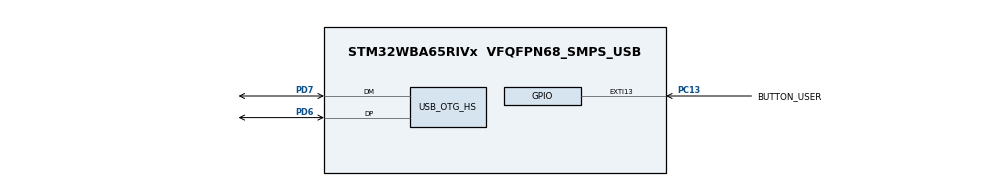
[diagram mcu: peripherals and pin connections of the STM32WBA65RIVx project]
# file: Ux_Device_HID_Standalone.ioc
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CORTEX_M33_NS.userName=CORTEX_M33
Mcu.Family=STM32WBA
Mcu.Name=STM32WBA65RIVx
Mcu.Package=VFQFPN68_SMPS_USB
NVIC.EXTI13_IRQn=true\:7\:0\:true\:false\:true\:true\:true\:true
NVIC.PriorityGroup=NVIC_PRIORITYGROUP_4
NVIC.USB_OTG_HS_IRQn=true\:6\:0\:true\:false\:true\:true\:true\:true
OSC_IN.Mode=HSE-External-Oscillator
OSC_IN.PinAttribute=CortexM33
OSC_IN.Signal=RCC_OSC_IN
OSC_OUT.Mode=HSE-External-Oscillator
OSC_OUT.PinAttribute=CortexM33
OSC_OUT.Signal=RCC_OSC_OUT
PC13.GPIO_Label=BUTTON_USER
PC13.GPIO_ModeDefaultEXTI=GPIO_MODE_IT_FALLING
PC13.GPIO_PuPd=GPIO_PULLUP
PC13.PinAttribute=Free
PC13.Signal=GPXTI13
PD6.Mode=Internal_Phy_Device
PD6.PinAttribute=CortexM33
PD6.Signal=USB_OTG_HS_DP
PD7.Mode=Internal_Phy_Device
PD7.PinAttribute=CortexM33
PD7.Signal=USB_OTG_HS_DM
ProjectManager.HeapSize=0x200
ProjectManager.StackSize=0x400
ProjectManager.TargetToolchain=EWARM V9.60
RCC.ADCFreq_Value=100000000
RCC.AHB5CLKDivider=DIV4
RCC.AHBFreq_Value=100000000
RCC.APB1Freq_Value=100000000
RCC.APB1TimFreq_Value=100000000
RCC.APB2Freq_Value=100000000
RCC.APB2TimFreq_Value=100000000
RCC.CortexFreq_Value=12500000
RCC.HCLKFreq_Value=100000000
RCC.HSE_VALUE=32000000
RCC.HSI_VALUE=16000000
RCC.LSE_VALUE=32768
RCC.LSI1_VALUE=32000
RCC.LSI2_VALUE=32000
RCC.PLLFRACN=4096
RCC.PLLM=2
RCC.PLLN=12
RCC.PLLSourceVirtual=RCC_PLLSOURCE_HSE
RCC.SYSCLKFreq_VALUE=100000000
RCC.SYSCLKSourceVirtual=RCC_SYSCLKSOURCE_PLLCLK
RCC.VCOOutputFreq_Value=200000000
USBX.BSP.number=1
USBX.Core_System=1
USBX.MAX_POWER_IN_MILLI_AMPER=0
USBX.REG_USBX_DEVICE_CON_CK=0
USBX.USBD_COMPOSITE_USE_IAD=0
USBX.USBD_PRODUCT_STRING=STM32 HID Mouse Device
USBX.USBD_SERIAL_NUMBER=HID001
USBX.USBX_SYS_SIZE=1024 * 4
USBX.UX_ALIGN_MIN=UX_ALIGN_8
USBX.UX_APP_MEM_POOL_SIZE_STANDALONE=1024 * 4
USBX.UX_DEVICE_ENABLED_HS=1
USBX.UX_DEVICE_HID_CORE=1
USBX.UX_DEVICE_HID_MOUSE=1
USBX.UX_Device_Controller=1
USBX.UX_Device_CoreStack=1
USBX.UX_MAX_SLAVE_CLASS_DRIVER=1
USBX.UX_SLAVE_REQUEST_DATA_MAX_LENGTH=512
USBX0.BSP.STBoard=false
USBX0.BSP.api=Unknown
USBX0.BSP.instance=USB_OTG_HS
USBX0.BSP.ip=USB_OTG_HS
USBX0.BSP.mode=Device_Only
USBX0.BSP.name=USB_Device
USBX0.BSP.solution=USB_OTG_HS
USB_OTG_HS.RefClockSelection=SYSCFG_OTG_HS_PHY_CLK_SELECT_6
USB_OTG_HS.VirtualMode=Device_HS
VP_CORTEX_M33_NS_VS_Hclk.Mode=Hclk_Mode
VP_ICACHE_VS_ICACHE.Mode=DirectMappedCache
VP_PWR_VS_SECSignals.Mode=Security/Privilege
VP_USBX_Core_System.Mode=Core_System
VP_USBX_UX\ Device\ Controller_HS.Mode=UX_Device_Controller_HS
VP_USBX_UX\ Device\ CoreStack_HS.Mode=UX_Device_CoreStack_HS
VP_USBX_UX\ Device\ HID_CORE_HS.Mode=UX_Device_class_HID_CORE_HS
VP_USBX_UX\ Device\ HID_MOUSE_HS.Mode=UX_Device_class_HID_MOUSE_HS
board=custom

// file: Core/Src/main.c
/* USER CODE BEGIN Header */
/**
  ******************************************************************************
  * @file           : main.c
  * @brief          : Main program body
  ******************************************************************************
  * @attention
  *
  * Copyright (c) 2024 STMicroelectronics.
  * All rights reserved.
  *
  * This software is licensed under terms that can be found in the LICENSE file
  * in the root directory of this software component.
  * If no LICENSE file comes with this software, it is provided AS-IS.
  *
  ******************************************************************************
  */
/* USER CODE END Header */
#include "main.h"
#include "app_usbx.h"

PCD_HandleTypeDef hpcd_USB_OTG_HS;

void SystemClock_Config(void);
static void MX_GPIO_Init(void);
static void MX_ICACHE_Init(void);

int main(void)
{

  /* MCU Configuration--------------------------------------------------------*/

  /* Reset of all peripherals, Initializes the Flash interface and the Systick. */
  HAL_Init();

  /* Configure the system clock */
  SystemClock_Config();

  /* Initialize all configured peripherals */
  MX_GPIO_Init();
  MX_ICACHE_Init();
  MX_USBX_Init();

  /* Infinite loop */
  while (1)
  {

    /* USER CODE BEGIN 3 */
    USBX_Device_Process(NULL);
  }
  /* USER CODE END 3 */
}

void SystemClock_Config(void)
{
  RCC_OscInitTypeDef RCC_OscInitStruct = {0};
  RCC_ClkInitTypeDef RCC_ClkInitStruct = {0};

  /** Supply configuration update enable
  */
  HAL_PWREx_ConfigSupply(PWR_LDO_SUPPLY);

  /** Configure the main internal regulator output voltage
  */
  if (HAL_PWREx_ControlVoltageScaling(PWR_REGULATOR_VOLTAGE_SCALE1) != HAL_OK)
  {
    Error_Handler();
  }

  /** Initializes the CPU, AHB and APB busses clocks
  */
  RCC_OscInitStruct.OscillatorType = RCC_OSCILLATORTYPE_HSE;
  RCC_OscInitStruct.HSEState = RCC_HSE_ON;
  RCC_OscInitStruct.HSEDiv = RCC_HSE_DIV1;
  RCC_OscInitStruct.PLL1.PLLState = RCC_PLL_ON;
  RCC_OscInitStruct.PLL1.PLLSource = RCC_PLLSOURCE_HSE;
  RCC_OscInitStruct.PLL1.PLLM = 2;
  RCC_OscInitStruct.PLL1.PLLN = 12;
  RCC_OscInitStruct.PLL1.PLLP = 2;
  RCC_OscInitStruct.PLL1.PLLQ = 2;
  RCC_OscInitStruct.PLL1.PLLR = 2;
  RCC_OscInitStruct.PLL1.PLLFractional = 4096;
  if (HAL_RCC_OscConfig(&RCC_OscInitStruct) != HAL_OK)
  {
    Error_Handler();
  }

  /** Initializes the CPU, AHB and APB busses clocks
  */
  RCC_ClkInitStruct.ClockType = RCC_CLOCKTYPE_HCLK|RCC_CLOCKTYPE_SYSCLK
                              |RCC_CLOCKTYPE_PCLK1|RCC_CLOCKTYPE_PCLK2
                              |RCC_CLOCKTYPE_PCLK7|RCC_CLOCKTYPE_HCLK5;
  RCC_ClkInitStruct.SYSCLKSource = RCC_SYSCLKSOURCE_PLLCLK;
  RCC_ClkInitStruct.AHBCLKDivider = RCC_SYSCLK_DIV1;
  RCC_ClkInitStruct.APB1CLKDivider = RCC_HCLK_DIV1;
  RCC_ClkInitStruct.APB2CLKDivider = RCC_HCLK_DIV1;
  RCC_ClkInitStruct.APB7CLKDivider = RCC_HCLK_DIV1;
  RCC_ClkInitStruct.AHB5_PLL1_CLKDivider = RCC_SYSCLK_PLL1_DIV4;
  RCC_ClkInitStruct.AHB5_HSEHSI_CLKDivider = RCC_SYSCLK_HSEHSI_DIV1;

  if (HAL_RCC_ClockConfig(&RCC_ClkInitStruct, FLASH_LATENCY_3) != HAL_OK)
  {
    Error_Handler();
  }
}

static void MX_ICACHE_Init(void)
{

  /** Enable instruction cache in 1-way (direct mapped cache)
  */
  if (HAL_ICACHE_ConfigAssociativityMode(ICACHE_1WAY) != HAL_OK)
  {
    Error_Handler();
  }
  if (HAL_ICACHE_Enable() != HAL_OK)
  {
    Error_Handler();
  }

}

void MX_USB_OTG_HS_PCD_Init(void)
{

  hpcd_USB_OTG_HS.Instance = USB_OTG_HS;
  hpcd_USB_OTG_HS.Init.dev_endpoints = 9;
  hpcd_USB_OTG_HS.Init.speed = PCD_SPEED_HIGH;
  hpcd_USB_OTG_HS.Init.phy_itface = USB_OTG_HS_EMBEDDED_PHY;
  hpcd_USB_OTG_HS.Init.Sof_enable = DISABLE;
  hpcd_USB_OTG_HS.Init.low_power_enable = DISABLE;
  hpcd_USB_OTG_HS.Init.lpm_enable = DISABLE;
  hpcd_USB_OTG_HS.Init.use_dedicated_ep1 = DISABLE;
  hpcd_USB_OTG_HS.Init.vbus_sensing_enable = DISABLE;
  hpcd_USB_OTG_HS.Init.dma_enable = DISABLE;
  if (HAL_PCD_Init(&hpcd_USB_OTG_HS) != HAL_OK)
  {
    Error_Handler();
  }
  /* USER CODE BEGIN USB_OTG_HS_PCD_Init 2 */
  /* Set Rx FIFO */
  HAL_PCDEx_SetRxFiFo(&hpcd_USB_OTG_HS, 0x200);

  /* Set Tx FIFO 0 */
  HAL_PCDEx_SetTxFiFo(&hpcd_USB_OTG_HS, 0, 0x10);

  /* Set Tx FIFO 1 */
  HAL_PCDEx_SetTxFiFo(&hpcd_USB_OTG_HS, 1, 0x10);

  /* USER CODE END USB_OTG_HS_PCD_Init 2 */

}

static void MX_GPIO_Init(void)
{
  GPIO_InitTypeDef GPIO_InitStruct = {0};

  /* GPIO Ports Clock Enable */
  __HAL_RCC_GPIOD_CLK_ENABLE();
  __HAL_RCC_GPIOC_CLK_ENABLE();

  /*Configure GPIO pin : BUTTON_USER_Pin */
  GPIO_InitStruct.Pin = BUTTON_USER_Pin;
  GPIO_InitStruct.Mode = GPIO_MODE_IT_FALLING;
  GPIO_InitStruct.Pull = GPIO_PULLUP;
  HAL_GPIO_Init(BUTTON_USER_GPIO_Port, &GPIO_InitStruct);

  /* EXTI interrupt init*/
  HAL_NVIC_SetPriority(BUTTON_USER_EXTI_IRQn, 7, 0);
  HAL_NVIC_EnableIRQ(BUTTON_USER_EXTI_IRQn);

}

void Error_Handler(void)
{
  while (1)
  {
  }
}

#ifdef USE_FULL_ASSERT
/**
  * @brief  Reports the name of the source file and the source line number
  *         where the assert_param error has occurred.
  * @param  file: pointer to the source file name
  * @param  line: assert_param error line source number
  * @retval None
  */
void assert_failed(uint8_t *file, uint32_t line)
{
  /* USER CODE BEGIN 6 */
  /* User can add his own implementation to report the file name and line number,
     ex: printf("Wrong parameters value: file %s on line %d\r\n", file, line) */
  /*Infinite loop */
  while (1)
  {
  }
  /* USER CODE END 6 */
}
#endif /* USE_FULL_ASSERT */
